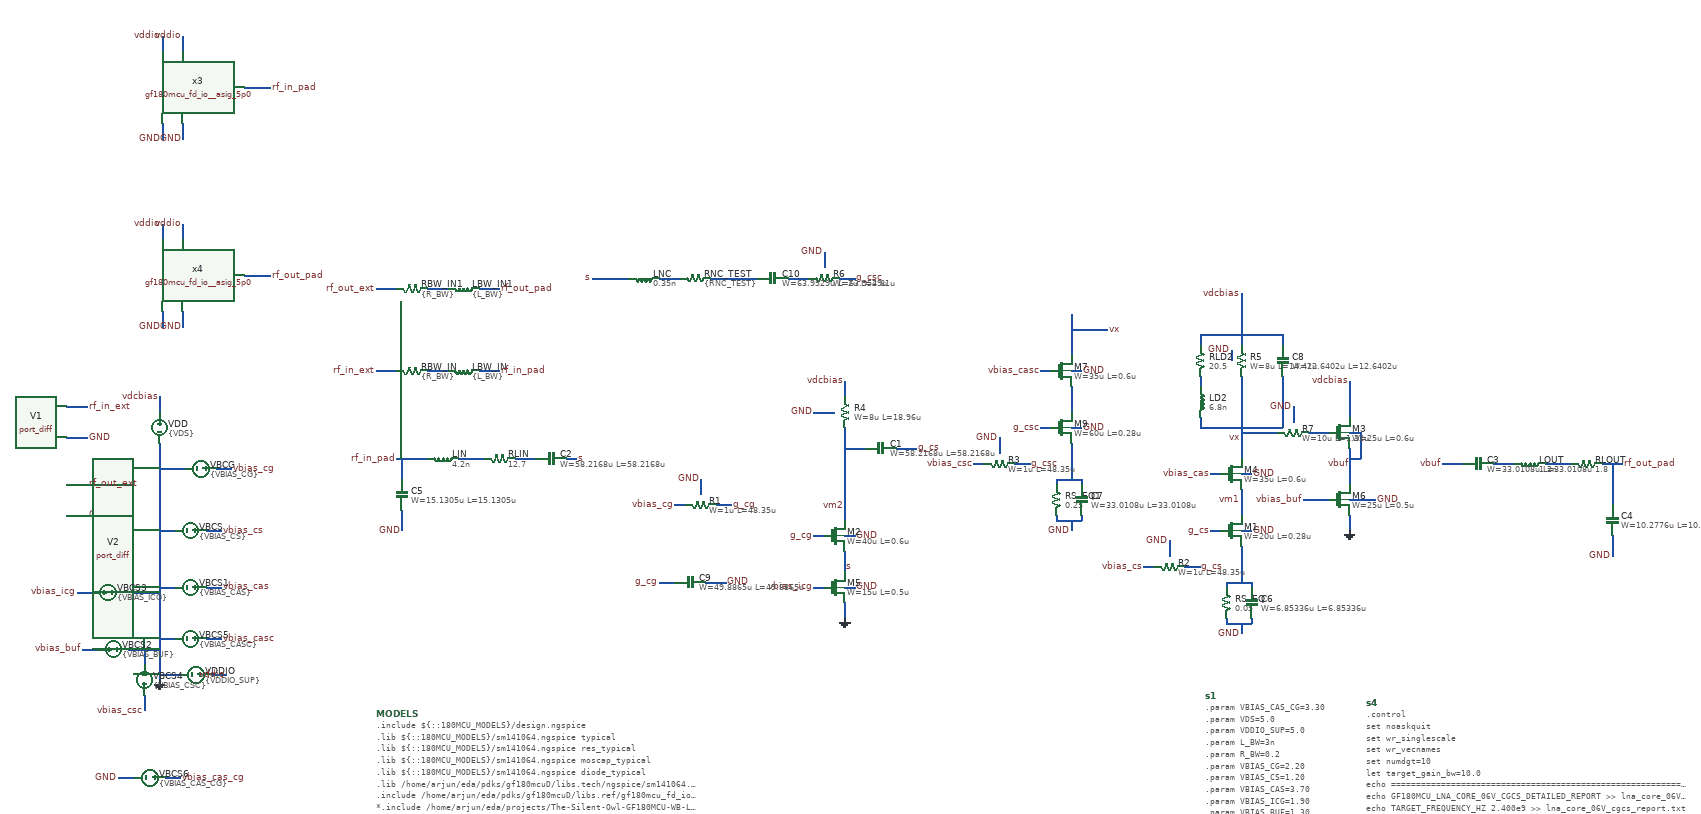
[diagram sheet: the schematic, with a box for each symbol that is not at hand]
v {xschem version=3.4.8RC file_version=1.3}
G {}
K {}
V {}
S {}
F {}
E {}
N -320 -440 -320 -410 {
lab=GND}
N 1010 -260 1030 -260 {
lab=GND}
N -320 -410 -320 -310 {
lab=GND}
N -320 -530 -320 -500 {
lab=vdcbias}
N -320 -390 -270 -390 {
lab=GND}
N -500 -510 -460 -510 {
lab=rf_in_ext}
N -500 -450 -460 -450 {
lab=GND}
N -500 -360 -460 -360 {
lab=rf_out_ext}
N -500 -300 -460 -300 {
lab=GND}
N 1010 -470 1010 -390 {
lab=vm2}
N 1010 -560 1010 -530 {
lab=vdcbias}
N -210 -390 -180 -390 {
lab=vbias_cg}
N 470 -410 490 -410 {
lab=s}
N 140 -410 170 -410 {
lab=rf_in_pad}
N 1010 -430 1050 -430 {
lab=vm2}
N 1110 -430 1150 -430 {
lab=g_cs}
N 1010 -230 1010 -220 {
lab=s}
N 1010 -220 1010 -190 {
lab=s}
N 950 -260 970 -260 {
lab=g_cg}
N -320 -310 -320 -110 {
lab=GND}
N 680 -320 700 -320 {
lab=vbias_cg}
N 760 -320 790 -320 {
lab=g_cg}
N 650 -170 680 -170 {
lab=g_cg}
N 740 -170 780 -170 {
lab=GND}
N 300 -580 340 -580 {
lab=rf_in_pad}
N 200 -580 240 -580 {
lab=#net1}
N 100 -580 140 -580 {
lab=rf_in_ext}
N -320 -270 -290 -270 {
lab=GND}
N -220 10 -190 10 {
lab=vddio}
N 300 -740 340 -740 {
lab=rf_out_pad}
N 200 -740 240 -740 {
lab=#net2}
N 100 -740 140 -740 {
lab=rf_out_ext}
N -320 10 -280 10 {
lab=GND}
N -230 -270 -200 -270 {
lab=vbias_cs}
N 1780 -270 1800 -270 {
lab=GND}
N 1780 -240 1780 -230 {
lab=#net3}
N 1720 -270 1740 -270 {
lab=g_cs}
N 1590 -200 1610 -200 {
lab=vbias_cs}
N 1670 -200 1700 -200 {
lab=g_cs}
N 1780 -230 1780 -170 {
lab=#net3}
N 1780 -670 1780 -630 {
lab=vdcbias}
N 1990 -560 1990 -490 {
lab=vdcbias}
N 1990 -430 1990 -360 {
lab=vbuf}
N 1990 -300 1990 -270 {
lab=GND}
N 1990 -460 2010 -460 {
lab=vbuf}
N 2170 -400 2210 -400 {
lab=vbuf}
N 2270 -400 2310 -400 {
lab=#net4}
N 2370 -400 2420 -400 {
lab=#net5}
N 2480 -400 2520 -400 {
lab=rf_out_pad}
N 2500 -400 2500 -320 {
lab=rf_out_pad}
N 2500 -260 2500 -220 {
lab=GND}
N 150 -410 150 -370 {
lab=rf_in_pad}
N 150 -310 150 -270 {
lab=GND}
N 170 -410 200 -410 {
lab=rf_in_pad}
N 260 -410 310 -410 {
lab=#net6}
N 370 -410 410 -410 {
lab=#net7}
N 1780 -380 1800 -380 {
lab=GND}
N 1780 -350 1780 -340 {
lab=vm1}
N 1720 -380 1740 -380 {
lab=vbias_cas}
N 1780 -570 1780 -490 {
lab=vx}
N 1780 -340 1780 -300 {
lab=vm1}
N -320 -110 -320 20 {
lab=GND}
N -230 -160 -200 -160 {
lab=vbias_cas}
N -320 -160 -290 -160 {
lab=GND}
N 2010 -460 2010 -410 {
lab=vbuf}
N 1990 -410 2010 -410 {
lab=vbuf}
N 1010 -160 1030 -160 {
lab=GND}
N 1010 -130 1010 -120 {
lab=GND}
N 950 -160 970 -160 {
lab=vbias_icg}
N 1010 -120 1010 -100 {
lab=GND}
N 1900 -330 1950 -330 {
lab=vbias_buf}
N 1990 -330 2040 -330 {
lab=GND}
N -470 -40 -440 -40 {
lab=vbias_buf}
N -380 -40 -320 -40 {
lab=GND}
N -480 -150 -450 -150 {
lab=vbias_icg}
N -390 -150 -320 -150 {
lab=GND}
N 1800 -170 1800 -160 {
lab=#net3}
N 1750 -170 1800 -170 {
lab=#net3}
N 1800 -100 1800 -90 {
lab=GND}
N 1750 -90 1800 -90 {
lab=GND}
N 1750 -170 1750 -160 {
lab=#net3}
N 1750 -100 1750 -90 {
lab=GND}
N 1780 -90 1780 -70 {
lab=GND}
N 1910 -460 1950 -460 {
lab=#net8}
N 1780 -460 1850 -460 {
lab=vx}
N -155 -1130 -105 -1130 {
lab=rf_in_pad
}
N -315 -1060 -315 -1030 {
lab=GND
}
N -275 -1060 -275 -1030 {
lab=GND
}
N -315 -1230 -315 -1200 {
lab=vddio
}
N -275 -1230 -275 -1200 {
lab=vddio
}
N -155 -765 -105 -765 {
lab=rf_out_pad
}
N -315 -695 -315 -665 {
lab=GND
}
N -275 -695 -275 -665 {
lab=GND
}
N -315 -865 -315 -835 {
lab=vddio
}
N -275 -865 -275 -835 {
lab=vddio
}
N 1450 -470 1470 -470 {
lab=GND}
N 1450 -440 1450 -430 {
lab=#net9}
N 1390 -470 1410 -470 {
lab=g_csc}
N 1260 -400 1280 -400 {
lab=vbias_csc}
N 1340 -400 1370 -400 {
lab=g_csc}
N 1450 -430 1450 -370 {
lab=#net9}
N 1450 -580 1470 -580 {
lab=GND}
N 1450 -550 1450 -540 {
lab=#net10}
N 1390 -580 1410 -580 {
lab=vbias_casc}
N 1450 -690 1450 -610 {
lab=vx}
N 1450 -540 1450 -500 {
lab=#net10}
N 1470 -370 1470 -360 {
lab=#net9}
N 1420 -370 1470 -370 {
lab=#net9}
N 1470 -300 1470 -290 {
lab=GND}
N 1420 -290 1470 -290 {
lab=GND}
N 1420 -370 1420 -360 {
lab=#net9}
N 1420 -300 1420 -290 {
lab=GND}
N 1450 -290 1450 -270 {
lab=GND}
N 1450 -660 1520 -660 {
lab=vx}
N -230 -270 -200 -270 {lab=vbias_cs}
N -350 -40 -350 -10 {
lab=GND}
N -350 50 -350 80 {
lab=vbias_csc}
N -230 -60 -200 -60 {
lab=vbias_casc}
N -320 -60 -290 -60 {
lab=GND}
N 650 -760 690 -760 {
lab=#net11}
N 900 -760 940 -760 {
lab=#net12}
N 1010 -330 1010 -320 {
lab=vm2}
N 1010 -320 1010 -290 {lab=vm2}
N -308.75 210 -278.75 210 {
lab=vbias_cas_cg}
N -400 210 -368.75 210 {
lab=GND}
N 1700 -650 1700 -630 {lab=vdcbias}
N 1700 -650 1780 -650 {lab=vdcbias}
N 1700 -570 1700 -550 {lab=#net13}
N 1860 -570 1860 -560 {lab=vx}
N 1780 -470 1860 -470 {lab=vx}
N 1860 -650 1860 -630 {lab=vdcbias}
N 1780 -650 1860 -650 {lab=vdcbias}
N 1860 -560 1860 -550 {lab=vx}
N 1010 -390 1010 -330 {lab=vm2}
N 1780 -490 1780 -410 {lab=vx}
N 1700 -490 1700 -470 {lab=vx}
N 1700 -470 1780 -470 {lab=vx}
N 1860 -550 1860 -470 {lab=vx}
N 520 -760 590 -760 {lab=s}
N 1000 -760 1030 -760 {lab=g_csc}
N 1640 -250 1640 -220 {lab=GND}
N 1310 -450 1310 -420 {lab=GND}
N 730 -370 730 -340 {lab=GND}
N 950 -500 990 -500 {lab=GND}
N 1760 -620 1760 -600 {lab=GND}
N 1780 -730 1780 -670 {lab=vdcbias}
N 970 -810 970 -780 {lab=GND}
N 1880 -510 1880 -480 {lab=GND}
N 750 -760 840 -760 {lab=#net14}
C {vsource.sym} -240 -390 1 0 {name=VBCG value=\{VBIAS_CG\} savecurrent=false}
C {gnd.sym} 1010 -100 0 0 {name=l1 lab=GND}
C {vsource.sym} -320 -470 0 0 {name=VDD value=\{VDS\} savecurrent=false}
C {lab_pin.sym} -460 -510 2 0 {name=p5 sig_type=std_logic lab=rf_in_ext}
C {lab_pin.sym} -460 -450 2 0 {name=p6 sig_type=std_logic lab=GND

}
C {lab_pin.sym} -460 -300 2 0 {name=p8 sig_type=std_logic lab=GND}
C {gnd.sym} -320 20 0 0 {name=l3 lab=GND}
C {lab_pin.sym} -320 -530 0 0 {name=p10 sig_type=std_logic lab=vdcbias
}
C {lab_pin.sym} -180 -390 2 0 {name=p9 sig_type=std_logic lab=vbias_cg}
C {lab_pin.sym} 1010 -560 0 0 {name=p11 sig_type=std_logic lab=vdcbias
}
C {lab_pin.sym} 1150 -430 2 0 {name=p14 sig_type=std_logic lab=g_cs}
C {port_diff.sym} -500 -480 0 0 {name=V1 portnum=1 Z0=50 DCval=0 ACmag=1 ACphase=0 TRANval=""}
C {port_diff.sym} -500 -330 0 0 {name=V2 portnum=2 Z0=50 DCval=0 ACmag=1 ACphase=0 TRANval=""}
C {lab_pin.sym} 1010 -200 2 0 {name=p1 sig_type=std_logic lab=s}
C {lab_pin.sym} 1030 -260 2 0 {name=p2 sig_type=std_logic lab=GND}
C {symbols/nfet_06v0.sym} 990 -260 0 0 {name=M2
L=0.6u
W=40u
nf=10
m=14
ad="'int((nf+1)/2) * W/nf * 0.18u'"
pd="'2*int((nf+1)/2) * (W/nf + 0.18u)'"
as="'int((nf+2)/2) * W/nf * 0.18u'"
ps="'2*int((nf+2)/2) * (W/nf + 0.18u)'"
nrd="'0.18u / W'" nrs="'0.18u / W'"
sa=0 sb=0 sd=0
model=nfet_06v0
spiceprefix=X
}
C {lab_pin.sym} 490 -410 2 0 {name=p17 sig_type=std_logic lab=s}
C {lab_pin.sym} 680 -320 0 0 {name=p20 sig_type=std_logic lab=vbias_cg}
C {lab_pin.sym} 790 -320 2 0 {name=p21 sig_type=std_logic lab=g_cg}
C {lab_pin.sym} 780 -170 2 0 {name=p19 sig_type=std_logic lab=GND}
C {ind.sym} 270 -580 1 0 {name=LBW_IN
m=1
value=\{L_BW\}
footprint=1206
device=inductor}
C {res.sym} 170 -580 1 0 {name=RBW_IN
value=\{R_BW\}
footprint=1206
device=resistor
m=1}
C {lab_pin.sym} 100 -580 0 0 {name=p22 sig_type=std_logic lab=rf_in_ext}
C {lab_pin.sym} 340 -580 2 0 {name=p25 sig_type=std_logic lab=rf_in_pad}
C {vsource.sym} -250 10 1 0 {name=VDDIO value=\{VDDIO_SUP\} savecurrent=false}
C {lab_pin.sym} -190 10 1 0 {name=p27 sig_type=std_logic lab=vddio
}
C {lab_pin.sym} 140 -410 0 0 {name=p13 sig_type=std_logic lab=rf_in_pad}
C {ind.sym} 270 -740 1 0 {name=LBW_IN1
m=1
value=\{L_BW\}
footprint=1206
device=inductor}
C {res.sym} 170 -740 1 0 {name=RBW_IN1
value=\{R_BW\}
footprint=1206
device=resistor
m=1}
C {lab_pin.sym} 100 -740 0 0 {name=p37 sig_type=std_logic lab=rf_out_ext}
C {lab_pin.sym} 340 -740 2 0 {name=p38 sig_type=std_logic lab=rf_out_pad}
C {lab_pin.sym} -460 -360 2 0 {name=p7 sig_type=std_logic lab=rf_out_ext}
C {vsource.sym} -260 -270 1 0 {name=VBCS value=\{VBIAS_CS\} savecurrent=false}
C {lab_pin.sym} -200 -270 2 0 {name=p12 sig_type=std_logic lab=vbias_cs}
C {lab_pin.sym} 950 -260 0 0 {name=p4 sig_type=std_logic lab=g_cg}
C {lab_pin.sym} 650 -170 0 0 {name=p15 sig_type=std_logic lab=g_cg}
C {lab_pin.sym} 1780 -70 3 0 {name=p16 sig_type=std_logic lab=GND}
C {lab_pin.sym} 1720 -270 0 0 {name=p18 sig_type=std_logic lab=g_cs}
C {lab_pin.sym} 1590 -200 0 0 {name=p23 sig_type=std_logic lab=vbias_cs}
C {lab_pin.sym} 1700 -200 2 0 {name=p24 sig_type=std_logic lab=g_cs}
C {lab_pin.sym} 1780 -730 0 0 {name=p39 sig_type=std_logic lab=vdcbias
}
C {symbols/nfet_06v0.sym} 1970 -460 0 0 {name=M3
L=0.6u
W=25u
nf=10
m=10
ad="'int((nf+1)/2) * W/nf * 0.18u'"
pd="'2*int((nf+1)/2) * (W/nf + 0.18u)'"
as="'int((nf+2)/2) * W/nf * 0.18u'"
ps="'2*int((nf+2)/2) * (W/nf + 0.18u)'"
nrd="'0.18u / W'" nrs="'0.18u / W'"
sa=0 sb=0 sd=0
model=nfet_06v0
spiceprefix=X
}
C {lab_pin.sym} 1990 -560 0 0 {name=p40 sig_type=std_logic lab=vdcbias
}
C {gnd.sym} 1990 -270 0 0 {name=l2 lab=GND}
C {lab_pin.sym} 1990 -400 0 0 {name=p43 sig_type=std_logic lab=vbuf}
C {lab_pin.sym} 2170 -400 0 0 {name=p44 sig_type=std_logic lab=vbuf}
C {lab_pin.sym} 2520 -400 2 0 {name=p45 sig_type=std_logic lab=rf_out_pad}
C {ind.sym} 2340 -400 1 0 {name=LOUT
m=1
value=1.2n
footprint=1206
device=inductor
}
C {res.sym} 2450 -400 1 0 {name=RLOUT
value=1.8
footprint=1206
device=resistor
m=1}
C {lab_pin.sym} 2500 -220 3 0 {name=p42 sig_type=std_logic lab=GND}
C {lab_pin.sym} 150 -270 3 0 {name=p46 sig_type=std_logic lab=GND}
C {ind.sym} 230 -410 1 0 {name=LIN
m=1
value=4.2n
footprint=1206
device=inductor
}
C {res.sym} 340 -410 1 0 {name=RLIN
value=12.7
footprint=1206
device=resistor
m=1}
C {symbols/nfet_06v0.sym} 1760 -380 0 0 {name=M4
L=0.6u
W=35u
nf=10
m=4
ad="'int((nf+1)/2) * W/nf * 0.18u'"
pd="'2*int((nf+1)/2) * (W/nf + 0.18u)'"
as="'int((nf+2)/2) * W/nf * 0.18u'"
ps="'2*int((nf+2)/2) * (W/nf + 0.18u)'"
nrd="'0.18u / W'" nrs="'0.18u / W'"
sa=0 sb=0 sd=0
model=nfet_06v0
spiceprefix=X
}
C {lab_pin.sym} 1720 -380 0 0 {name=p47 sig_type=std_logic lab=vbias_cas}
C {lab_pin.sym} 1800 -380 2 0 {name=p48 sig_type=std_logic lab=GND}
C {vsource.sym} -260 -160 1 0 {name=VBCS1 value=\{VBIAS_CAS\} savecurrent=false}
C {lab_pin.sym} -200 -160 2 0 {name=p49 sig_type=std_logic lab=vbias_cas}
C {lab_pin.sym} 1030 -160 2 0 {name=p41 sig_type=std_logic lab=GND}
C {lab_pin.sym} 950 -160 0 0 {name=p50 sig_type=std_logic lab=vbias_icg}
C {lab_pin.sym} 1900 -330 0 0 {name=p51 sig_type=std_logic lab=vbias_buf}
C {lab_pin.sym} 2040 -330 2 0 {name=p52 sig_type=std_logic lab=GND}
C {vsource.sym} -410 -40 3 0 {name=VBCS2 value=\{VBIAS_BUF\} savecurrent=false}
C {lab_pin.sym} -470 -40 0 0 {name=p53 sig_type=std_logic lab=vbias_buf}
C {vsource.sym} -420 -150 3 0 {name=VBCS3 value=\{VBIAS_ICG\} savecurrent=false}
C {lab_pin.sym} -480 -150 0 0 {name=p54 sig_type=std_logic lab=vbias_icg}
C {symbols/nfet_03v3.sym} 990 -160 0 0 {name=M5
L=0.5u
W=15u
nf=10
m=1
ad="'int((nf+1)/2) * W/nf * 0.18u'"
pd="'2*int((nf+1)/2) * (W/nf + 0.18u)'"
as="'int((nf+2)/2) * W/nf * 0.18u'"
ps="'2*int((nf+2)/2) * (W/nf + 0.18u)'"
nrd="'0.18u / W'" nrs="'0.18u / W'"
sa=0 sb=0 sd=0
model=nfet_03v3
spiceprefix=X
}
C {symbols/nfet_03v3.sym} 1970 -330 0 0 {name=M6
L=0.5u
W=25u
nf=10
m=5
ad="'int((nf+1)/2) * W/nf * 0.18u'"
pd="'2*int((nf+1)/2) * (W/nf + 0.18u)'"
as="'int((nf+2)/2) * W/nf * 0.18u'"
ps="'2*int((nf+2)/2) * (W/nf + 0.18u)'"
nrd="'0.18u / W'" nrs="'0.18u / W'"
sa=0 sb=0 sd=0
model=nfet_03v3
spiceprefix=X
}
C {res.sym} 1750 -130 0 0 {name=RS_EQ
value=0.05
footprint=1206
device=resistor
m=1
}
C {lab_pin.sym} 1800 -270 2 0 {name=p55 sig_type=std_logic lab=GND}
C {symbols/nfet_03v3.sym} 1760 -270 0 0 {name=M1
L=0.28u
W=20u
nf=10
m=10
ad="'int((nf+1)/2) * W/nf * 0.18u'"
pd="'2*int((nf+1)/2) * (W/nf + 0.18u)'"
as="'int((nf+2)/2) * W/nf * 0.18u'"
ps="'2*int((nf+2)/2) * (W/nf + 0.18u)'"
nrd="'0.18u / W'" nrs="'0.18u / W'"
sa=0 sb=0 sd=0
model=nfet_03v3
spiceprefix=X
}
C {lab_pin.sym} -105 -1130 2 0 {name=p56 sig_type=std_logic lab=rf_in_pad
}
C {lab_pin.sym} -315 -1230 1 0 {name=p57 sig_type=std_logic lab=vddio
}
C {lab_pin.sym} -275 -1230 1 0 {name=p58 sig_type=std_logic lab=vddio
}
C {lab_pin.sym} -315 -1030 3 0 {name=p59 sig_type=std_logic lab=GND
}
C {lab_pin.sym} -275 -1030 3 0 {name=p60 sig_type=std_logic lab=GND
}
C {/home/arjun/eda/projects/The-Silent-Owl-GF180MCU-WB-LNA/analog_pad_sp_paramerters/xschem/gf180mcu_fd_io__asig_5p0.sym} -305 -1130 0 0 {name=x3 model=gf180mcu_fd_io__asig_5p0
}
C {lab_pin.sym} -315 -865 1 0 {name=p61 sig_type=std_logic lab=vddio
}
C {lab_pin.sym} -275 -865 1 0 {name=p62 sig_type=std_logic lab=vddio
}
C {lab_pin.sym} -315 -665 3 0 {name=p63 sig_type=std_logic lab=GND
}
C {lab_pin.sym} -275 -665 3 0 {name=p64 sig_type=std_logic lab=GND
}
C {lab_pin.sym} -105 -765 2 0 {name=p65 sig_type=std_logic lab=rf_out_pad
}
C {/home/arjun/eda/projects/The-Silent-Owl-GF180MCU-WB-LNA/analog_pad_sp_paramerters/xschem/gf180mcu_fd_io__asig_5p0.sym} -305 -765 0 0 {name=x4 model=gf180mcu_fd_io__asig_5p0
}
C {lab_pin.sym} 1450 -270 3 0 {name=p26 sig_type=std_logic lab=GND}
C {lab_pin.sym} 1390 -470 0 0 {name=p28 sig_type=std_logic lab=g_csc}
C {lab_pin.sym} 1260 -400 0 0 {name=p29 sig_type=std_logic lab=vbias_csc}
C {lab_pin.sym} 1370 -400 2 0 {name=p30 sig_type=std_logic lab=g_csc}
C {symbols/nfet_06v0.sym} 1430 -580 0 0 {name=M7
L=0.6u
W=35u
nf=10
m=2
ad="'int((nf+1)/2) * W/nf * 0.18u'"
pd="'2*int((nf+1)/2) * (W/nf + 0.18u)'"
as="'int((nf+2)/2) * W/nf * 0.18u'"
ps="'2*int((nf+2)/2) * (W/nf + 0.18u)'"
nrd="'0.18u / W'" nrs="'0.18u / W'"
sa=0 sb=0 sd=0
model=nfet_06v0
spiceprefix=X
}
C {lab_pin.sym} 1390 -580 0 0 {name=p32 sig_type=std_logic lab=vbias_casc}
C {lab_pin.sym} 1470 -580 2 0 {name=p33 sig_type=std_logic lab=GND}
C {res.sym} 1420 -330 0 0 {name=RS_EQ1
value=0.25
footprint=1206
device=resistor
m=1
}
C {lab_pin.sym} 1470 -470 2 0 {name=p34 sig_type=std_logic lab=GND}
C {symbols/nfet_03v3.sym} 1430 -470 0 0 {name=M9
L=0.28u
W=60u
nf=4
m=4
ad="'int((nf+1)/2) * W/nf * 0.18u'"
pd="'2*int((nf+1)/2) * (W/nf + 0.18u)'"
as="'int((nf+2)/2) * W/nf * 0.18u'"
ps="'2*int((nf+2)/2) * (W/nf + 0.18u)'"
nrd="'0.18u / W'" nrs="'0.18u / W'"
sa=0 sb=0 sd=0
model=nfet_03v3
spiceprefix=X
}
C {vsource.sym} -350 20 2 0 {name=VBCS4 value=\{VBIAS_CSC\} savecurrent=false}
C {lab_pin.sym} -350 80 3 0 {name=p35 sig_type=std_logic lab=vbias_csc}
C {lab_pin.sym} 1780 -450 0 0 {name=p36 sig_type=std_logic lab=vx}
C {lab_pin.sym} 1520 -660 2 0 {name=p66 sig_type=std_logic lab=vx}
C {vsource.sym} -260 -60 1 0 {name=VBCS5 value=\{VBIAS_CASC\} savecurrent=false}
C {lab_pin.sym} -200 -60 2 0 {name=p67 sig_type=std_logic lab=vbias_casc}
C {lab_pin.sym} 1030 -760 2 0 {name=p68 sig_type=std_logic lab=g_csc}
C {lab_pin.sym} 520 -760 0 0 {name=p69 sig_type=std_logic lab=s}
C {code_shown.sym} 100 85 0 0 {name=MODELS only_toplevel=true
format="tcleval( @value )"
value="
.include $\{::180MCU_MODELS\}/design.ngspice

.lib $\{::180MCU_MODELS\}/sm141064.ngspice typical

.lib $\{::180MCU_MODELS\}/sm141064.ngspice res_typical
.lib $\{::180MCU_MODELS\}/sm141064.ngspice moscap_typical
.lib $\{::180MCU_MODELS\}/sm141064.ngspice diode_typical

.lib /home/arjun/eda/pdks/gf180mcuD/libs.tech/ngspice/sm141064.ngspice mimcap_typical
.include /home/arjun/eda/pdks/gf180mcuD/libs.ref/gf180mcu_fd_io/spice/gf180mcu_fd_io.spice
*.include /home/arjun/eda/projects/The-Silent-Owl-GF180MCU-WB-LNA/analog_pad_sp_paramerters/spice_files/extracted_gf180mcu_fd_io__asig_5p0.spice
"}
C {lab_pin.sym} 1010 -318.75 0 0 {name=p71 sig_type=std_logic lab=vm2}
C {lab_pin.sym} 1780 -328.75 0 0 {name=p72 sig_type=std_logic lab=vm1}
C {vsource.sym} -338.75 210 1 0 {name=VBCS6 value=\{VBIAS_CAS_CG\} savecurrent=false}
C {lab_pin.sym} -278.75 210 2 0 {name=p73 sig_type=std_logic lab=vbias_cas_cg}
C {lab_pin.sym} -400 210 0 0 {name=p74 sig_type=std_logic lab=GND}
C {ind.sym} 1700 -520 0 0 {name=LD2
m=1
value=6.8n
footprint=1206
device=inductor
}
C {res.sym} 1700 -600 0 0 {name=RLD2
value=20.5
footprint=1206
device=resistor
m=1
}
C {ind.sym} 620 -760 3 1 {name=LNC
m=1
value=0.35n
footprint=1206
device=inductor
}
C {code_shown.sym} 1710 50 0 0 {name=s1 only_toplevel=false value="
.param VBIAS_CAS_CG=3.30



.param VDS=5.0
.param VDDIO_SUP=5.0

.param L_BW=3n
.param R_BW=0.2


.param VBIAS_CG=2.20
.param VBIAS_CS=1.20

.param VBIAS_CAS=3.70
.param VBIAS_ICG=1.90
.param VBIAS_BUF=1.30

.param VBIAS_CSC=0.90


.param VBIAS_CASC=3.20
.param RNC_TEST=1m

"}
C {code.sym} 2022.5 63.75 0 0 {name=s4 only_toplevel=false value="

.control

set noaskquit
set wr_singlescale
set wr_vecnames
set numdgt=10

let target_gain_bw=10.0

echo ============================================================ > lna_core_06V_cgcs_report.txt
echo GF180MCU_LNA_CORE_06V_CGCS_DETAILED_REPORT >> lna_core_06V_cgcs_report.txt
echo TARGET_FREQUENCY_HZ 2.400e9 >> lna_core_06V_cgcs_report.txt
echo TARGET_BAND_HZ 2.300e9 2.500e9 >> lna_core_06V_cgcs_report.txt
echo GAIN_BANDWIDTH_THRESHOLD_DB 10.0 >> lna_core_06V_cgcs_report.txt
echo PORT_REFERENCE_OHM 50 >> lna_core_06V_cgcs_report.txt
echo ============================================================ >> lna_core_06V_cgcs_report.txt

* =============================================================================
* DC OPERATING POINT
* =============================================================================

op

let pdcop=1e3*(abs(i(VDD))*v(vdcbias)+abs(i(VDDIO))*v(vddio))
let icoreop=abs(i(VDD))
let iioop=abs(i(VDDIO))

let vsop=v(s)
let vdop=v(vm2)
let vnet3op=v(net3)
let vnet8op=v(net8)
let vbufop=v(vbuf)
let vgcsop=v(g_cs)
let vgcgop=v(g_cg)

let id1op=abs(@m.xm1.m0[id])
let gm1op=@m.xm1.m0[gm]
let gmb1op=@m.xm1.m0[gmbs]
let gds1op=@m.xm1.m0[gds]
let vgs1op=@m.xm1.m0[vgs]
let vds1op=@m.xm1.m0[vds]
let vbs1op=@m.xm1.m0[vbs]
let vth1op=@m.xm1.m0[vth]
let vov1op=vgs1op-vth1op
let vdsat1op=abs(@m.xm1.m0[vdsat])
let sat1op=vds1op-vdsat1op
let gmid1op=gm1op/(id1op+1e-30)
let ro1op=1/(gds1op+1e-30)

let id2op=abs(@m.xm2.m0[id])
let gm2op=@m.xm2.m0[gm]
let gmb2op=@m.xm2.m0[gmbs]
let gds2op=@m.xm2.m0[gds]
let vgs2op=@m.xm2.m0[vgs]
let vds2op=@m.xm2.m0[vds]
let vbs2op=@m.xm2.m0[vbs]
let vth2op=@m.xm2.m0[vth]
let vov2op=vgs2op-vth2op
let vdsat2op=abs(@m.xm2.m0[vdsat])
let sat2op=vds2op-vdsat2op
let gmid2op=gm2op/(id2op+1e-30)
let ro2op=1/(gds2op+1e-30)

let id3op=abs(@m.xm3.m0[id])
let gm3op=@m.xm3.m0[gm]
let gmb3op=@m.xm3.m0[gmbs]
let gds3op=@m.xm3.m0[gds]
let vgs3op=@m.xm3.m0[vgs]
let vds3op=@m.xm3.m0[vds]
let vbs3op=@m.xm3.m0[vbs]
let vth3op=@m.xm3.m0[vth]
let vov3op=vgs3op-vth3op
let vdsat3op=abs(@m.xm3.m0[vdsat])
let sat3op=vds3op-vdsat3op
let gmid3op=gm3op/(id3op+1e-30)
let ro3op=1/(gds3op+1e-30)

let id4op=abs(@m.xm4.m0[id])
let gm4op=@m.xm4.m0[gm]
let gmb4op=@m.xm4.m0[gmbs]
let gds4op=@m.xm4.m0[gds]
let vgs4op=@m.xm4.m0[vgs]
let vds4op=@m.xm4.m0[vds]
let vbs4op=@m.xm4.m0[vbs]
let vth4op=@m.xm4.m0[vth]
let vov4op=vgs4op-vth4op
let vdsat4op=abs(@m.xm4.m0[vdsat])
let sat4op=vds4op-vdsat4op
let gmid4op=gm4op/(id4op+1e-30)
let ro4op=1/(gds4op+1e-30)

let id5op=abs(@m.xm5.m0[id])
let gm5op=@m.xm5.m0[gm]
let gmb5op=@m.xm5.m0[gmbs]
let gds5op=@m.xm5.m0[gds]
let vgs5op=@m.xm5.m0[vgs]
let vds5op=@m.xm5.m0[vds]
let vbs5op=@m.xm5.m0[vbs]
let vth5op=@m.xm5.m0[vth]
let vov5op=vgs5op-vth5op
let vdsat5op=abs(@m.xm5.m0[vdsat])
let sat5op=vds5op-vdsat5op
let gmid5op=gm5op/(id5op+1e-30)
let ro5op=1/(gds5op+1e-30)

let id6op=abs(@m.xm6.m0[id])
let gm6op=@m.xm6.m0[gm]
let gmb6op=@m.xm6.m0[gmbs]
let gds6op=@m.xm6.m0[gds]
let vgs6op=@m.xm6.m0[vgs]
let vds6op=@m.xm6.m0[vds]
let vbs6op=@m.xm6.m0[vbs]
let vth6op=@m.xm6.m0[vth]
let vov6op=vgs6op-vth6op
let vdsat6op=abs(@m.xm6.m0[vdsat])
let sat6op=vds6op-vdsat6op
let gmid6op=gm6op/(id6op+1e-30)
let ro6op=1/(gds6op+1e-30)

let id7op=abs(@m.xm7.m0[id])
let gm7op=@m.xm7.m0[gm]
let gmb7op=@m.xm7.m0[gmbs]
let gds7op=@m.xm7.m0[gds]
let vgs7op=@m.xm7.m0[vgs]
let vds7op=@m.xm7.m0[vds]
let vbs7op=@m.xm7.m0[vbs]
let vth7op=@m.xm7.m0[vth]
let vov7op=vgs7op-vth7op
let vdsat7op=abs(@m.xm7.m0[vdsat])
let sat7op=vds7op-vdsat7op
let gmid7op=gm7op/(id7op+1e-30)
let ro7op=1/(gds7op+1e-30)

let id9op=abs(@m.xm9.m0[id])
let gm9op=@m.xm9.m0[gm]
let gmb9op=@m.xm9.m0[gmbs]
let gds9op=@m.xm9.m0[gds]
let vgs9op=@m.xm9.m0[vgs]
let vds9op=@m.xm9.m0[vds]
let vbs9op=@m.xm9.m0[vbs]
let vth9op=@m.xm9.m0[vth]
let vov9op=vgs9op-vth9op
let vdsat9op=abs(@m.xm9.m0[vdsat])
let sat9op=vds9op-vdsat9op
let gmid9op=gm9op/(id9op+1e-30)
let ro9op=1/(gds9op+1e-30)

let vnet9op=vnet3op+vds1op
let vnet9check=vnet8op-vds4op
let vnet9diff=vnet9op-vnet9check
let vnet10op=vsop+vds2op
let vnet10check=vdop-vds7op
let vnet10diff=vnet10op-vnet10check

set op_pdc=$&pdcop
set op_icore=$&icoreop
set op_iio=$&iioop
set op_vs=$&vsop
set op_vnet10=$&vnet10op
set op_vnet10check=$&vnet10check
set op_vnet10diff=$&vnet10diff
set op_vd=$&vdop
set op_vnet3=$&vnet3op
set op_vnet9=$&vnet9op
set op_vnet9check=$&vnet9check
set op_vnet9diff=$&vnet9diff
set op_vnet8=$&vnet8op
set op_vbuf=$&vbufop
set op_vgcs=$&vgcsop
set op_vgcg=$&vgcgop

set op_id1=$&id1op
set op_gm1=$&gm1op
set op_gmb1=$&gmb1op
set op_gds1=$&gds1op
set op_vgs1=$&vgs1op
set op_vds1=$&vds1op
set op_vbs1=$&vbs1op
set op_vth1=$&vth1op
set op_vov1=$&vov1op
set op_vdsat1=$&vdsat1op
set op_sat1=$&sat1op
set op_gmid1=$&gmid1op
set op_ro1=$&ro1op

set op_id2=$&id2op
set op_gm2=$&gm2op
set op_gmb2=$&gmb2op
set op_gds2=$&gds2op
set op_vgs2=$&vgs2op
set op_vds2=$&vds2op
set op_vbs2=$&vbs2op
set op_vth2=$&vth2op
set op_vov2=$&vov2op
set op_vdsat2=$&vdsat2op
set op_sat2=$&sat2op
set op_gmid2=$&gmid2op
set op_ro2=$&ro2op

set op_id3=$&id3op
set op_gm3=$&gm3op
set op_gmb3=$&gmb3op
set op_gds3=$&gds3op
set op_vgs3=$&vgs3op
set op_vds3=$&vds3op
set op_vbs3=$&vbs3op
set op_vth3=$&vth3op
set op_vov3=$&vov3op
set op_vdsat3=$&vdsat3op
set op_sat3=$&sat3op
set op_gmid3=$&gmid3op
set op_ro3=$&ro3op

set op_id4=$&id4op
set op_gm4=$&gm4op
set op_gmb4=$&gmb4op
set op_gds4=$&gds4op
set op_vgs4=$&vgs4op
set op_vds4=$&vds4op
set op_vbs4=$&vbs4op
set op_vth4=$&vth4op
set op_vov4=$&vov4op
set op_vdsat4=$&vdsat4op
set op_sat4=$&sat4op
set op_gmid4=$&gmid4op
set op_ro4=$&ro4op

set op_id5=$&id5op
set op_gm5=$&gm5op
set op_gmb5=$&gmb5op
set op_gds5=$&gds5op
set op_vgs5=$&vgs5op
set op_vds5=$&vds5op
set op_vbs5=$&vbs5op
set op_vth5=$&vth5op
set op_vov5=$&vov5op
set op_vdsat5=$&vdsat5op
set op_sat5=$&sat5op
set op_gmid5=$&gmid5op
set op_ro5=$&ro5op

set op_id6=$&id6op
set op_gm6=$&gm6op
set op_gmb6=$&gmb6op
set op_gds6=$&gds6op
set op_vgs6=$&vgs6op
set op_vds6=$&vds6op
set op_vbs6=$&vbs6op
set op_vth6=$&vth6op
set op_vov6=$&vov6op
set op_vdsat6=$&vdsat6op
set op_sat6=$&sat6op
set op_gmid6=$&gmid6op
set op_ro6=$&ro6op

set op_id7=$&id7op
set op_gm7=$&gm7op
set op_gmb7=$&gmb7op
set op_gds7=$&gds7op
set op_vgs7=$&vgs7op
set op_vds7=$&vds7op
set op_vbs7=$&vbs7op
set op_vth7=$&vth7op
set op_vov7=$&vov7op
set op_vdsat7=$&vdsat7op
set op_sat7=$&sat7op
set op_gmid7=$&gmid7op
set op_ro7=$&ro7op

set op_id9=$&id9op
set op_gm9=$&gm9op
set op_gmb9=$&gmb9op
set op_gds9=$&gds9op
set op_vgs9=$&vgs9op
set op_vds9=$&vds9op
set op_vbs9=$&vbs9op
set op_vth9=$&vth9op
set op_vov9=$&vov9op
set op_vdsat9=$&vdsat9op
set op_sat9=$&sat9op
set op_gmid9=$&gmid9op
set op_ro9=$&ro9op

echo ============================================================ >> lna_core_06V_cgcs_report.txt
echo DC_SUPPLY_AND_NODE_VOLTAGES >> lna_core_06V_cgcs_report.txt
echo PDC_mW $op_pdc ICORE_A $op_icore IIO_A $op_iio >> lna_core_06V_cgcs_report.txt
echo NODES_V S $op_vs NET10_DERIVED $op_vnet10 VM2 $op_vd NET3 $op_vnet3 NET9_DERIVED $op_vnet9 NET8 $op_vnet8 VBUF $op_vbuf G_CS $op_vgcs G_CG $op_vgcg >> lna_core_06V_cgcs_report.txt
echo HIDDEN_NODE_CHECKS NET10_FROM_XM2 $op_vnet10 NET10_FROM_XM7 $op_vnet10check DIFFERENCE $op_vnet10diff NET9_FROM_XM1 $op_vnet9 NET9_FROM_XM4 $op_vnet9check DIFFERENCE $op_vnet9diff >> lna_core_06V_cgcs_report.txt
echo ============================================================ >> lna_core_06V_cgcs_report.txt
echo TRANSISTOR_OPERATING_POINTS >> lna_core_06V_cgcs_report.txt
echo FIELDS ID_A GM_S GMBS_S GDS_S VGS_V VDS_V VBS_V VTH_V VOV_V VDSAT_V SAT_MARGIN_V GM_OVER_ID_1_PER_V RO_OHM >> lna_core_06V_cgcs_report.txt
echo XM1_CS ID $op_id1 GM $op_gm1 GMBS $op_gmb1 GDS $op_gds1 VGS $op_vgs1 VDS $op_vds1 VBS $op_vbs1 VTH $op_vth1 VOV $op_vov1 VDSAT $op_vdsat1 SAT_MARGIN $op_sat1 GMID $op_gmid1 RO $op_ro1 >> lna_core_06V_cgcs_report.txt
echo XM2_CG ID $op_id2 GM $op_gm2 GMBS $op_gmb2 GDS $op_gds2 VGS $op_vgs2 VDS $op_vds2 VBS $op_vbs2 VTH $op_vth2 VOV $op_vov2 VDSAT $op_vdsat2 SAT_MARGIN $op_sat2 GMID $op_gmid2 RO $op_ro2 >> lna_core_06V_cgcs_report.txt
echo XM3_SOURCE_FOLLOWER ID $op_id3 GM $op_gm3 GMBS $op_gmb3 GDS $op_gds3 VGS $op_vgs3 VDS $op_vds3 VBS $op_vbs3 VTH $op_vth3 VOV $op_vov3 VDSAT $op_vdsat3 SAT_MARGIN $op_sat3 GMID $op_gmid3 RO $op_ro3 >> lna_core_06V_cgcs_report.txt
echo XM4_CS_CASCODE ID $op_id4 GM $op_gm4 GMBS $op_gmb4 GDS $op_gds4 VGS $op_vgs4 VDS $op_vds4 VBS $op_vbs4 VTH $op_vth4 VOV $op_vov4 VDSAT $op_vdsat4 SAT_MARGIN $op_sat4 GMID $op_gmid4 RO $op_ro4 >> lna_core_06V_cgcs_report.txt
echo XM5_CG_CURRENT_SINK ID $op_id5 GM $op_gm5 GMBS $op_gmb5 GDS $op_gds5 VGS $op_vgs5 VDS $op_vds5 VBS $op_vbs5 VTH $op_vth5 VOV $op_vov5 VDSAT $op_vdsat5 SAT_MARGIN $op_sat5 GMID $op_gmid5 RO $op_ro5 >> lna_core_06V_cgcs_report.txt
echo XM6_BUFFER_CURRENT_SINK ID $op_id6 GM $op_gm6 GMBS $op_gmb6 GDS $op_gds6 VGS $op_vgs6 VDS $op_vds6 VBS $op_vbs6 VTH $op_vth6 VOV $op_vov6 VDSAT $op_vdsat6 SAT_MARGIN $op_sat6 GMID $op_gmid6 RO $op_ro6 >> lna_core_06V_cgcs_report.txt
echo XM7_CG_CASCODE ID $op_id7 GM $op_gm7 GMBS $op_gmb7 GDS $op_gds7 VGS $op_vgs7 VDS $op_vds7 VBS $op_vbs7 VTH $op_vth7 VOV $op_vov7 VDSAT $op_vdsat7 SAT_MARGIN $op_sat7 GMID $op_gmid7 RO $op_ro7 >> lna_core_06V_cgcs_report.txt
echo XM9_CANCELLATION_CS ID $op_id9 GM $op_gm9 GMBS $op_gmb9 GDS $op_gds9 VGS $op_vgs9 VDS $op_vds9 VBS $op_vbs9 VTH $op_vth9 VOV $op_vov9 VDSAT $op_vdsat9 SAT_MARGIN $op_sat9 GMID $op_gmid9 RO $op_ro9 >> lna_core_06V_cgcs_report.txt

destroy $curplot

* =============================================================================
* SINGLE BROADBAND RF ANALYSIS
* One reset and one SP run are used for all 1 MHz to 7 GHz RF results.
* Target-band values are extracted from the same dataset.
* This avoids inconsistent port excitation state between repeated SP runs.
* 7000 points from 1 MHz to 7 GHz gives exactly 1 MHz spacing.
* =============================================================================

reset
sp lin 7000 1Meg 7Gig 1
set rfplot=$curplot

let fghz=frequency/1e9

let s11db=db(s_1_1)
let s21db=db(s_2_1)
let s12db=db(s_1_2)
let s22db=db(s_2_2)

let s11re=real(s_1_1)
let s11im=imag(s_1_1)
let s21re=real(s_2_1)
let s21im=imag(s_2_1)
let s12re=real(s_1_2)
let s12im=imag(s_1_2)
let s22re=real(s_2_2)
let s22im=imag(s_2_2)

let nfdb=real(NF)
let nfmin_db=real(NFmin)

let delta=s_1_1*s_2_2-s_1_2*s_2_1
let delta_mag=mag(delta)
let a11=mag(s_1_1)
let a12=mag(s_1_2)
let a21=mag(s_2_1)
let a22=mag(s_2_2)
let mu=(1-a11*a11)/(mag(s_2_2-delta*conj(s_1_1))+mag(s_1_2*s_2_1))
let mup=(1-a22*a22)/(mag(s_1_1-delta*conj(s_2_2))+mag(s_1_2*s_2_1))
let kval=(1-a11*a11-a22*a22+delta_mag*delta_mag)/(2*a12*a21)

let zin=50*(1+s_1_1)/(1-s_1_1)
let zout=50*(1+s_2_2)/(1-s_2_2)
let zin_re=real(zin)
let zin_im=imag(zin)
let zout_re=real(zout)
let zout_im=imag(zout)

let npts=length(frequency)

* Find indices nearest 2.300 GHz, 2.400 GHz and 2.500 GHz.
let ilo=0
let icenter=0
let ihi=0
let errlo=abs(frequency[0]-2.3e9)
let errcenter=abs(frequency[0]-2.4e9)
let errhi=abs(frequency[0]-2.5e9)
let ii=1
while ii < npts
let newerr=abs(frequency[ii]-2.3e9)
if newerr < errlo
let errlo=newerr
let ilo=ii
end
let newerr=abs(frequency[ii]-2.4e9)
if newerr < errcenter
let errcenter=newerr
let icenter=ii
end
let newerr=abs(frequency[ii]-2.5e9)
if newerr < errhi
let errhi=newerr
let ihi=ii
end
let ii=ii+1
end

* Values at the sample nearest 2.400 GHz.
let center_freq=frequency[icenter]
let s11c=s11db[icenter]
let s21c=s21db[icenter]
let s12c=s12db[icenter]
let s22c=s22db[icenter]
let s11rc=s11re[icenter]
let s11ic=s11im[icenter]
let s21rc=s21re[icenter]
let s21ic=s21im[icenter]
let s12rc=s12re[icenter]
let s12ic=s12im[icenter]
let s22rc=s22re[icenter]
let s22ic=s22im[icenter]
let nfc=nfdb[icenter]
let nfminc=nfmin_db[icenter]
let muc=mu[icenter]
let mupc=mup[icenter]
let kc=kval[icenter]
let dmc=delta_mag[icenter]
let zinrc=zin_re[icenter]
let zinic=zin_im[icenter]
let zoutrc=zout_re[icenter]
let zoutic=zout_im[icenter]

* Initialize target-band extrema.
let s11min=s11db[ilo]
let s11max=s11db[ilo]
let s21min=s21db[ilo]
let s21max=s21db[ilo]
let s12min=s12db[ilo]
let s12max=s12db[ilo]
let s22min=s22db[ilo]
let s22max=s22db[ilo]
let nfbandmin=nfdb[ilo]
let nfbandmax=nfdb[ilo]
let nfminbandmin=nfmin_db[ilo]
let nfminbandmax=nfmin_db[ilo]
let mumin=mu[ilo]
let mupmin=mup[ilo]
let kmin=kval[ilo]
let dmax=delta_mag[ilo]

let s11min_i=ilo
let s11max_i=ilo
let s21min_i=ilo
let s21max_i=ilo
let s12min_i=ilo
let s12max_i=ilo
let s22min_i=ilo
let s22max_i=ilo
let nfmin_i=ilo
let nfmax_i=ilo
let nfminpar_min_i=ilo
let nfminpar_max_i=ilo
let mumin_i=ilo
let mupmin_i=ilo
let kmin_i=ilo
let dmax_i=ilo

* Scan 2.300 GHz to 2.500 GHz.
let ii=ilo
while ii <= ihi
if s11db[ii] < s11min
let s11min=s11db[ii]
let s11min_i=ii
end
if s11db[ii] > s11max
let s11max=s11db[ii]
let s11max_i=ii
end
if s21db[ii] < s21min
let s21min=s21db[ii]
let s21min_i=ii
end
if s21db[ii] > s21max
let s21max=s21db[ii]
let s21max_i=ii
end
if s12db[ii] < s12min
let s12min=s12db[ii]
let s12min_i=ii
end
if s12db[ii] > s12max
let s12max=s12db[ii]
let s12max_i=ii
end
if s22db[ii] < s22min
let s22min=s22db[ii]
let s22min_i=ii
end
if s22db[ii] > s22max
let s22max=s22db[ii]
let s22max_i=ii
end
if nfdb[ii] < nfbandmin
let nfbandmin=nfdb[ii]
let nfmin_i=ii
end
if nfdb[ii] > nfbandmax
let nfbandmax=nfdb[ii]
let nfmax_i=ii
end
if nfmin_db[ii] < nfminbandmin
let nfminbandmin=nfmin_db[ii]
let nfminpar_min_i=ii
end
if nfmin_db[ii] > nfminbandmax
let nfminbandmax=nfmin_db[ii]
let nfminpar_max_i=ii
end
if mu[ii] < mumin
let mumin=mu[ii]
let mumin_i=ii
end
if mup[ii] < mupmin
let mupmin=mup[ii]
let mupmin_i=ii
end
if kval[ii] < kmin
let kmin=kval[ii]
let kmin_i=ii
end
if delta_mag[ii] > dmax
let dmax=delta_mag[ii]
let dmax_i=ii
end
let ii=ii+1
end

let gain_ripple=s21max-s21min

let s11min_f=frequency[s11min_i]
let s11max_f=frequency[s11max_i]
let s21min_f=frequency[s21min_i]
let s21max_f=frequency[s21max_i]
let s12min_f=frequency[s12min_i]
let s12max_f=frequency[s12max_i]
let s22min_f=frequency[s22min_i]
let s22max_f=frequency[s22max_i]
let nfmin_f=frequency[nfmin_i]
let nfmax_f=frequency[nfmax_i]
let nfminpar_min_f=frequency[nfminpar_min_i]
let nfminpar_max_f=frequency[nfminpar_max_i]
let mumin_f=frequency[mumin_i]
let mupmin_f=frequency[mupmin_i]
let kmin_f=frequency[kmin_i]
let dmax_f=frequency[dmax_i]

* Find the broadband S21 peak and its index.
let imax=0
let gainmax=s21db[0]
let ii=1
while ii < npts
if s21db[ii] > gainmax
let gainmax=s21db[ii]
let imax=ii
end
let ii=ii+1
end
let peakfreq=frequency[imax]

echo ============================================================ >> lna_core_06V_cgcs_report.txt
echo RF_AT_2P400_GHZ_FROM_SINGLE_BROADBAND_SWEEP >> lna_core_06V_cgcs_report.txt
echo ACTUAL_SAMPLE_HZ $&center_freq >> lna_core_06V_cgcs_report.txt
echo S11_DB $&s11c REAL $&s11rc IMAG $&s11ic >> lna_core_06V_cgcs_report.txt
echo S21_DB $&s21c REAL $&s21rc IMAG $&s21ic >> lna_core_06V_cgcs_report.txt
echo S12_DB $&s12c REAL $&s12rc IMAG $&s12ic >> lna_core_06V_cgcs_report.txt
echo S22_DB $&s22c REAL $&s22rc IMAG $&s22ic >> lna_core_06V_cgcs_report.txt
echo NF_DB $&nfc NFMIN_DB $&nfminc >> lna_core_06V_cgcs_report.txt
echo MU $&muc MUP $&mupc K $&kc DELTA_MAG $&dmc >> lna_core_06V_cgcs_report.txt
echo ZIN_OHM RE $&zinrc IM $&zinic >> lna_core_06V_cgcs_report.txt
echo ZOUT_OHM RE $&zoutrc IM $&zoutic >> lna_core_06V_cgcs_report.txt

echo ============================================================ >> lna_core_06V_cgcs_report.txt
echo RF_MIN_MAX_FROM_2P300_TO_2P500_GHZ >> lna_core_06V_cgcs_report.txt
echo S11_MIN_DB $&s11min AT_HZ $&s11min_f S11_MAX_DB $&s11max AT_HZ $&s11max_f >> lna_core_06V_cgcs_report.txt
echo S21_MIN_DB $&s21min AT_HZ $&s21min_f S21_MAX_DB $&s21max AT_HZ $&s21max_f GAIN_RIPPLE_DB $&gain_ripple >> lna_core_06V_cgcs_report.txt
echo S12_MIN_DB $&s12min AT_HZ $&s12min_f S12_MAX_DB $&s12max AT_HZ $&s12max_f >> lna_core_06V_cgcs_report.txt
echo S22_MIN_DB $&s22min AT_HZ $&s22min_f S22_MAX_DB $&s22max AT_HZ $&s22max_f >> lna_core_06V_cgcs_report.txt
echo NF_MIN_DB $&nfbandmin AT_HZ $&nfmin_f NF_MAX_DB $&nfbandmax AT_HZ $&nfmax_f >> lna_core_06V_cgcs_report.txt
echo NFMIN_PARAMETER_MIN_DB $&nfminbandmin AT_HZ $&nfminpar_min_f NFMIN_PARAMETER_MAX_DB $&nfminbandmax AT_HZ $&nfminpar_max_f >> lna_core_06V_cgcs_report.txt
echo MU_MIN $&mumin AT_HZ $&mumin_f MUP_MIN $&mupmin AT_HZ $&mupmin_f >> lna_core_06V_cgcs_report.txt
echo K_MIN $&kmin AT_HZ $&kmin_f DELTA_MAX $&dmax AT_HZ $&dmax_f >> lna_core_06V_cgcs_report.txt

echo ============================================================ >> lna_core_06V_cgcs_report.txt
echo BROADBAND_GAIN_CHECK_1MHZ_TO_7GHZ >> lna_core_06V_cgcs_report.txt
echo GAIN_AT_2P4_DB $&s21c >> lna_core_06V_cgcs_report.txt
echo BROADBAND_PEAK_HZ $&peakfreq PEAK_GAIN_DB $&gainmax >> lna_core_06V_cgcs_report.txt

echo ============================================================ >> lna_core_06V_cgcs_report.txt
echo TARGET_CENTERED_S21_GE_10DB_BAND >> lna_core_06V_cgcs_report.txt
if s21c >= 10.0
let bwlo=icenter
let bwhi=icenter
let search=1
while search = 1
if bwlo > 0
if s21db[bwlo-1] >= 10.0
let bwlo=bwlo-1
else
let search=0
end
else
let search=0
end
end
let search=1
while search = 1
if bwhi < npts-1
if s21db[bwhi+1] >= 10.0
let bwhi=bwhi+1
else
let search=0
end
else
let search=0
end
end
let bwflo=frequency[bwlo]
let bwfhi=frequency[bwhi]
let bwval=bwfhi-bwflo
let bwcenter=0.5*(bwfhi+bwflo)
let bwfbw=100*bwval/(bwcenter+1e-30)
echo LOWER_HZ $&bwflo UPPER_HZ $&bwfhi BANDWIDTH_HZ $&bwval BAND_CENTER_HZ $&bwcenter FRACTIONAL_BW_PERCENT $&bwfbw >> lna_core_06V_cgcs_report.txt
else
echo NO_VALID_TARGET_CENTERED_BAND S21_AT_2P4_DB $&s21c >> lna_core_06V_cgcs_report.txt
end

echo ============================================================ >> lna_core_06V_cgcs_report.txt
echo GLOBAL_CONTIGUOUS_S21_GE_10DB_BAND_AROUND_PEAK >> lna_core_06V_cgcs_report.txt
if gainmax >= 10.0
let bwlo=imax
let bwhi=imax
let search=1
while search = 1
if bwlo > 0
if s21db[bwlo-1] >= 10.0
let bwlo=bwlo-1
else
let search=0
end
else
let search=0
end
end
let search=1
while search = 1
if bwhi < npts-1
if s21db[bwhi+1] >= 10.0
let bwhi=bwhi+1
else
let search=0
end
else
let search=0
end
end
let bwflo=frequency[bwlo]
let bwfhi=frequency[bwhi]
let bwval=bwfhi-bwflo
let bwcenter=0.5*(bwfhi+bwflo)
let bwfbw=100*bwval/(bwcenter+1e-30)
echo LOWER_HZ $&bwflo UPPER_HZ $&bwfhi BANDWIDTH_HZ $&bwval BAND_CENTER_HZ $&bwcenter FRACTIONAL_BW_PERCENT $&bwfbw >> lna_core_06V_cgcs_report.txt
else
echo NO_S21_ABOVE_10DB_FROM_1MHZ_TO_7GHZ PEAK_GAIN_DB $&gainmax PEAK_FREQUENCY_HZ $&peakfreq >> lna_core_06V_cgcs_report.txt
end

wrdata lna_core_06V_cgcs_target_band.dat frequency s_1_1 s_2_1 s_1_2 s_2_2 s11db s21db s12db s22db nfdb nfmin_db kval mu mup delta_mag zin_re zin_im zout_re zout_im
wrdata lna_core_06V_cgcs_broadband.dat frequency s11db s21db s12db s22db nfdb nfmin_db kval mu mup delta_mag zin_re zin_im zout_re zout_im

* =============================================================================
* NOISE-CANCELLATION A/B PROOF
*
* ON baseline:
*   CNC = optimized value (8.2 pF).
*
* OFF baseline:
*   CNC is opened to 1e-18 F using alterparam.
*   XM7/XM9 remain biased and connected to vx, so their DC current,
*   output loading and intrinsic noise remain present. Only the sensed
*   RF path from node s to g_csc is removed. This is a conservative
*   demonstration of whether the sensing/cancellation action reduces NF.
*
* Positive NF_IMPROVEMENT_DB = NF_OFF - NF_ON means cancellation helps.
* =============================================================================

* Preserve the cancellation-ON plot generated above.
set nc_on_plot=$rfplot

* Open only the noise-sensing capacitor.
alterparam RNC_TEST = 1e15
reset

sp lin 7000 1Meg 7Gig 1
set nc_off_plot=$curplot

let fghz_nc=frequency/1e9

* Copy ON data into this plot so ON and OFF vectors share one scale.
let nf_nc_on=\{$nc_on_plot\}.nfdb
let s21_nc_on=\{$nc_on_plot\}.s21db
let s11_nc_on=\{$nc_on_plot\}.s11db
let s22_nc_on=\{$nc_on_plot\}.s22db

* OFF data with the cancellation sensing path opened.
let nf_nc_off=real(NF)
let s21_nc_off=db(s_2_1)
let s11_nc_off=db(s_1_1)
let s22_nc_off=db(s_2_2)

* Main proof vector. Positive values mean lower NF with cancellation ON.
let nf_improvement_db=nf_nc_off-nf_nc_on
let gain_change_on_minus_off_db=s21_nc_on-s21_nc_off

let nc_npts=length(frequency)

* Locate 2.3, 2.4 and 2.5 GHz in the OFF dataset.
let nc_ilo=0
let nc_icenter=0
let nc_ihi=0
let nc_errlo=abs(frequency[0]-2.3e9)
let nc_errcenter=abs(frequency[0]-2.4e9)
let nc_errhi=abs(frequency[0]-2.5e9)
let nc_ii=1
while nc_ii < nc_npts
  let nc_newerr=abs(frequency[nc_ii]-2.3e9)
  if nc_newerr < nc_errlo
    let nc_errlo=nc_newerr
    let nc_ilo=nc_ii
  end

  let nc_newerr=abs(frequency[nc_ii]-2.4e9)
  if nc_newerr < nc_errcenter
    let nc_errcenter=nc_newerr
    let nc_icenter=nc_ii
  end

  let nc_newerr=abs(frequency[nc_ii]-2.5e9)
  if nc_newerr < nc_errhi
    let nc_errhi=nc_newerr
    let nc_ihi=nc_ii
  end

  let nc_ii=nc_ii+1
end

* Center-frequency results.
let nc_freq_center=frequency[nc_icenter]
let nc_nf_on_c=nf_nc_on[nc_icenter]
let nc_nf_off_c=nf_nc_off[nc_icenter]
let nc_imp_c=nf_improvement_db[nc_icenter]

let nc_s21_on_c=s21_nc_on[nc_icenter]
let nc_s21_off_c=s21_nc_off[nc_icenter]
let nc_gain_delta_c=gain_change_on_minus_off_db[nc_icenter]

let nc_s11_on_c=s11_nc_on[nc_icenter]
let nc_s11_off_c=s11_nc_off[nc_icenter]
let nc_s22_on_c=s22_nc_on[nc_icenter]
let nc_s22_off_c=s22_nc_off[nc_icenter]

* Improvement extrema over 2.3-2.5 GHz.
let nc_imp_min=nf_improvement_db[nc_ilo]
let nc_imp_max=nf_improvement_db[nc_ilo]
let nc_imp_min_i=nc_ilo
let nc_imp_max_i=nc_ilo

let nc_ii=nc_ilo
while nc_ii <= nc_ihi
  if nf_improvement_db[nc_ii] < nc_imp_min
    let nc_imp_min=nf_improvement_db[nc_ii]
    let nc_imp_min_i=nc_ii
  end
  if nf_improvement_db[nc_ii] > nc_imp_max
    let nc_imp_max=nf_improvement_db[nc_ii]
    let nc_imp_max_i=nc_ii
  end
  let nc_ii=nc_ii+1
end

let nc_imp_min_f=frequency[nc_imp_min_i]
let nc_imp_max_f=frequency[nc_imp_max_i]

* User-selectable threshold for a practically meaningful center improvement.
let nc_practical_threshold_db=0.20

echo ============================================================ >> lna_core_06V_cgcs_report.txt
echo NOISE_CANCELLATION_AB_PROOF >> lna_core_06V_cgcs_report.txt
echo METHOD ON_CNC_8P2PF OFF_CNC_1E_MINUS18F_XM7_XM9_STILL_BIASED_AND_LOADING_RETAINED >> lna_core_06V_cgcs_report.txt
echo ACTUAL_CENTER_SAMPLE_HZ $&nc_freq_center >> lna_core_06V_cgcs_report.txt
echo NF_ON_DB $&nc_nf_on_c NF_OFF_DB $&nc_nf_off_c NF_IMPROVEMENT_DB $&nc_imp_c >> lna_core_06V_cgcs_report.txt
echo S21_ON_DB $&nc_s21_on_c S21_OFF_DB $&nc_s21_off_c S21_ON_MINUS_OFF_DB $&nc_gain_delta_c >> lna_core_06V_cgcs_report.txt
echo S11_ON_DB $&nc_s11_on_c S11_OFF_DB $&nc_s11_off_c >> lna_core_06V_cgcs_report.txt
echo S22_ON_DB $&nc_s22_on_c S22_OFF_DB $&nc_s22_off_c >> lna_core_06V_cgcs_report.txt
echo NF_IMPROVEMENT_MIN_DB_2P3_TO_2P5 $&nc_imp_min AT_HZ $&nc_imp_min_f >> lna_core_06V_cgcs_report.txt
echo NF_IMPROVEMENT_MAX_DB_2P3_TO_2P5 $&nc_imp_max AT_HZ $&nc_imp_max_f >> lna_core_06V_cgcs_report.txt
echo PRACTICAL_CENTER_THRESHOLD_DB $&nc_practical_threshold_db >> lna_core_06V_cgcs_report.txt

if nc_imp_c > 0
  echo CENTER_DIRECTIONAL_TEST PASS_CANCELLATION_LOWERS_NF >> lna_core_06V_cgcs_report.txt
else
  echo CENTER_DIRECTIONAL_TEST FAIL_CANCELLATION_DOES_NOT_LOWER_NF >> lna_core_06V_cgcs_report.txt
end

if nc_imp_min > 0
  echo FULL_TARGET_BAND_TEST PASS_CANCELLATION_LOWERS_NF_ACROSS_2P3_TO_2P5_GHZ >> lna_core_06V_cgcs_report.txt
else
  echo FULL_TARGET_BAND_TEST FAIL_NF_IMPROVEMENT_NOT_POSITIVE_ACROSS_ENTIRE_TARGET_BAND >> lna_core_06V_cgcs_report.txt
end

if nc_imp_c >= nc_practical_threshold_db
  echo PRACTICAL_CENTER_TEST PASS_IMPROVEMENT_AT_LEAST_0P20_DB >> lna_core_06V_cgcs_report.txt
else
  echo PRACTICAL_CENTER_TEST FAIL_IMPROVEMENT_BELOW_0P20_DB >> lna_core_06V_cgcs_report.txt
end

wrdata lna_core_06V_cgcs_noise_cancellation.dat nf_nc_on nf_nc_off nf_improvement_db s21_nc_on s21_nc_off s11_nc_on s11_nc_off s22_nc_on s22_nc_off

* Restore the optimized cancellation capacitor before subsequent analyses.
alterparam RNC_TEST = 1m
reset

* =============================================================================
* WIDEBAND STABILITY 10 MHZ TO 30 GHZ
* =============================================================================

sp dec 101 10Meg 30G 1
set stabilityplot=$curplot

let wbdelta=s_1_1*s_2_2-s_1_2*s_2_1
let wbmd=mag(wbdelta)
let wba11=mag(s_1_1)
let wba12=mag(s_1_2)
let wba21=mag(s_2_1)
let wba22=mag(s_2_2)
let wbmu=(1-wba11*wba11)/(mag(s_2_2-wbdelta*conj(s_1_1))+mag(s_1_2*s_2_1))
let wbmup=(1-wba22*wba22)/(mag(s_1_1-wbdelta*conj(s_2_2))+mag(s_1_2*s_2_1))
let wbk=(1-wba11*wba11-wba22*wba22+wbmd*wbmd)/(2*wba12*wba21)

let wbkmin=minimum(wbk)
let wbmumin=minimum(wbmu)
let wbmupmin=minimum(wbmup)
let wbdmax=maximum(wbmd)

set final_wbkmin=$&wbkmin
set final_wbmumin=$&wbmumin
set final_wbmupmin=$&wbmupmin
set final_wbdmax=$&wbdmax

echo ============================================================ >> lna_core_06V_cgcs_report.txt
echo WIDEBAND_STABILITY_10MHZ_TO_30GHZ >> lna_core_06V_cgcs_report.txt
echo K_MIN $final_wbkmin MU_MIN $final_wbmumin MUP_MIN $final_wbmupmin DELTA_MAX $final_wbdmax >> lna_core_06V_cgcs_report.txt

wrdata lna_core_06V_cgcs_stability.dat frequency wbk wbmu wbmup wbmd

let wbfghz=frequency/1e9

echo ============================================================ >> lna_core_06V_cgcs_report.txt
echo OUTPUT_FILES >> lna_core_06V_cgcs_report.txt
echo REPORT lna_core_06V_cgcs_report.txt >> lna_core_06V_cgcs_report.txt
echo TARGET_DATA lna_core_06V_cgcs_target_band.dat >> lna_core_06V_cgcs_report.txt
echo BROADBAND_DATA lna_core_06V_cgcs_broadband.dat >> lna_core_06V_cgcs_report.txt
echo STABILITY_DATA lna_core_06V_cgcs_stability.dat >> lna_core_06V_cgcs_report.txt
echo NOISE_CANCELLATION_DATA lna_core_06V_cgcs_noise_cancellation.dat >> lna_core_06V_cgcs_report.txt
echo PLOTS S_PARAMETERS NF_NFMIN NOISE_CANCELLATION_ON_OFF NF_IMPROVEMENT S21_ON_OFF >> lna_core_06V_cgcs_report.txt
echo ============================================================ >> lna_core_06V_cgcs_report.txt



* =============================================================================
* VISIBLE PLOTS
* Plot commands are intentionally placed at the very end.
* Neither rfplot nor stabilityplot is destroyed or reset afterward.
* =============================================================================

setplot $rfplot
setscale fghz

* Target band 2.3 GHz to 2.5 GHz
plot s11db xlimit 2.3 2.5
plot s21db xlimit 2.3 2.5
plot s12db xlimit 2.3 2.5
plot s22db xlimit 2.3 2.5
plot nfdb nfmin_db xlimit 2.3 2.5
* plot mu mup xlimit 2.3 2.5
* plot kval xlimit 2.3 2.5
* plot delta_mag xlimit 2.3 2.5
* plot zin_re zin_im xlimit 2.3 2.5
* plot zout_re zout_im xlimit 2.3 2.5

* Broadband 1 MHz to 7 GHz
plot s11db xlimit 0 7
plot s21db xlimit 0 7
plot s12db xlimit 0 7
plot s22db xlimit 0 7
plot nfdb nfmin_db xlimit 0 7
* plot mu mup xlimit 0 7
* plot kval xlimit 0 7
* plot delta_mag xlimit 0 7
* plot zin_re zin_im xlimit 0 7
* plot zout_re zout_im xlimit 0 7

* Noise-cancellation proof plots
setplot $nc_off_plot
setscale fghz_nc
set xbrushwidth=2

* Plot 1: direct NF comparison; ON must lie below OFF.
plot nf_nc_on nf_nc_off xlimit 2.3 2.5 xlabel 'Frequency (GHz)' ylabel 'Noise figure (dB)'

* Plot 2: positive improvement proves cancellation benefit.
plot nf_improvement_db xlimit 2.3 2.5 xlabel 'Frequency (GHz)' ylabel 'NF OFF - NF ON (dB)'

* Plot 3: signal-gain sanity check for the same A/B experiment.
plot s21_nc_on s21_nc_off xlimit 2.3 2.5 xlabel 'Frequency (GHz)' ylabel 'S21 (dB)'

* Wideband stability 10 MHz to 30 GHz
* setplot $stabilityplot
* setscale wbfghz
* plot wbmu wbmup
* plot wbk
* plot wbmd

.endc

"
}
C {symbols/ppolyf_u_1k.sym} 1640 -200 1 0 {name=R2
W=1u
L=48.35u
model=ppolyf_u_1k
spiceprefix=X
m=1}
C {lab_pin.sym} 1640 -250 1 0 {name=p31 sig_type=std_logic lab=GND}
C {symbols/ppolyf_u_1k.sym} 1310 -400 1 0 {name=R3
W=1u
L=48.35u
model=ppolyf_u_1k
spiceprefix=X
m=1}
C {lab_pin.sym} 1310 -450 1 0 {name=p70 sig_type=std_logic lab=GND}
C {symbols/ppolyf_u_1k.sym} 730 -320 1 0 {name=R1
W=1u
L=48.35u
model=ppolyf_u_1k
spiceprefix=X
m=1}
C {lab_pin.sym} 730 -370 1 0 {name=p3 sig_type=std_logic lab=GND}
C {symbols/ppolyf_u.sym} 1010 -500 0 0 {name=R4
W=8u
L=18.96u
model=ppolyf_u
spiceprefix=X
m=1}
C {lab_pin.sym} 950 -500 0 0 {name=p75 sig_type=std_logic lab=GND}
C {symbols/ppolyf_u.sym} 1780 -600 0 0 {name=R5
W=8u
L=14.42u
model=ppolyf_u
spiceprefix=X
m=1}
C {lab_pin.sym} 1760 -620 1 0 {name=p76 sig_type=std_logic lab=GND}
C {symbols/npolyf_s.sym} 970 -760 1 0 {name=R6
W=2u
L=4.81u
model=npolyf_s
spiceprefix=X
m=1}
C {lab_pin.sym} 970 -810 1 0 {name=p77 sig_type=std_logic lab=GND}
C {symbols/npolyf_s.sym} 1880 -460 1 0 {name=R7
W=10u
L=1.32u
model=npolyf_s
spiceprefix=X
m=1}
C {lab_pin.sym} 1880 -510 1 0 {name=p78 sig_type=std_logic lab=GND}
C {symbols/cap_mim_2f0fF.sym} 1080 -430 1 0 {name=C1
W=58.2168u
L=58.2168u
model=cap_mim_2f0_m4m5_noshield
spiceprefix=X
m=1}
C {symbols/cap_mim_2f0fF.sym} 440 -410 1 0 {name=C2
W=58.2168u
L=58.2168u
model=cap_mim_2f0_m4m5_noshield
spiceprefix=X
m=1}
C {symbols/cap_mim_2f0fF.sym} 2240 -400 1 0 {name=C3
W=33.0108u
L=33.0108u
model=cap_mim_2f0_m4m5_noshield
spiceprefix=X
m=1}
C {symbols/cap_mim_2f0fF.sym} 2500 -290 0 0 {name=C4
W=10.2776u
L=10.2776u
model=cap_mim_2f0_m4m5_noshield
spiceprefix=X
m=1}
C {symbols/cap_mim_2f0fF.sym} 150 -340 0 0 {name=C5
W=15.1305u
L=15.1305u
model=cap_mim_2f0_m4m5_noshield
spiceprefix=X
m=1}
C {symbols/cap_mim_2f0fF.sym} 1800 -130 0 0 {name=C6
W=6.85336u
L=6.85336u
model=cap_mim_2f0_m4m5_noshield
spiceprefix=X
m=1}
C {symbols/cap_mim_2f0fF.sym} 1470 -330 0 0 {name=C7
W=33.0108u
L=33.0108u
model=cap_mim_2f0_m4m5_noshield
spiceprefix=X
m=1}
C {symbols/cap_mim_2f0fF.sym} 1860 -600 0 0 {name=C8
W=12.6402u
L=12.6402u
model=cap_mim_2f0_m4m5_noshield
spiceprefix=X
m=1}
C {symbols/cap_mim_2f0fF.sym} 710 -170 1 0 {name=C9
W=49.8865u
L=49.8865u
model=cap_mim_2f0_m4m5_noshield
spiceprefix=X
m=4}
C {symbols/cap_mim_2f0fF.sym} 870 -760 3 0 {name=C10
W=63.9529u
L=63.9529u
model=cap_mim_2f0_m4m5_noshield
spiceprefix=X
m=1}
C {res.sym} 720 -760 1 0 {name=RNC_TEST
value=\{RNC_TEST\}
footprint=1206
device=resistor
m=1}
